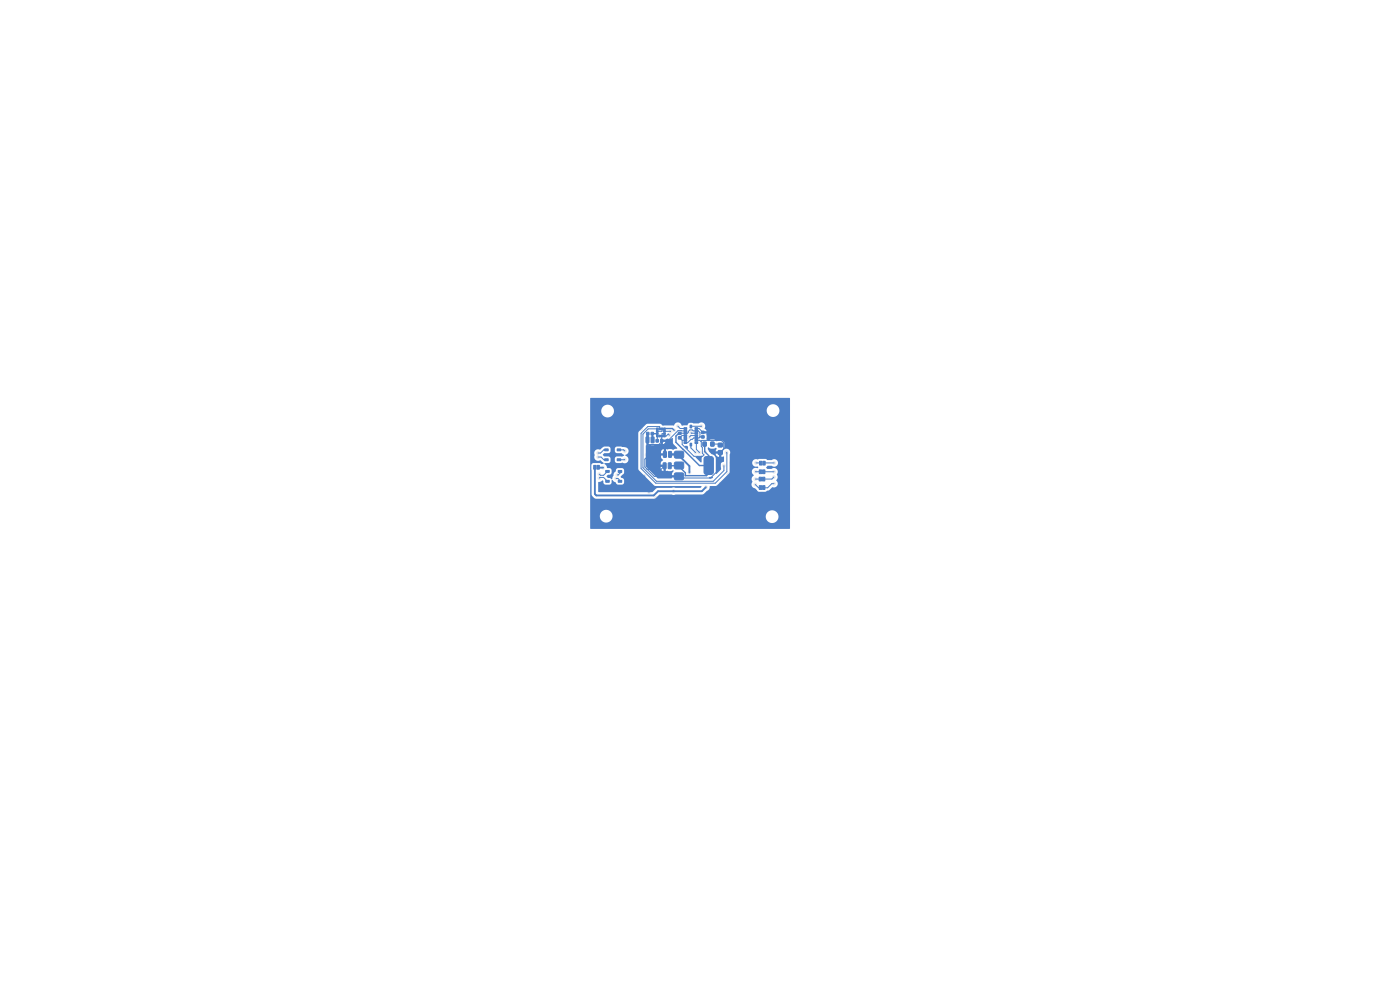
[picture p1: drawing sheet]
<svg xmlns="http://www.w3.org/2000/svg" width="297mm" height="210mm" viewBox="0 0 297 210" stroke-linecap="round" stroke-linejoin="round" font-family="sans-serif">
<g fill="#4d7fc4" stroke="#4d7fc4" stroke-width=".21">
<path d="M148.8 92.4h.6v.5h-.6z"/>
<path d="M148.8 91.5h.6v.5h-.6z"/>
<path d="M138.1 91.7h.5v.6h-.5z"/>
<path d="M137.2 91.7h.5v.6h-.5z"/>
<path d="M126.6 98.7h.6v.8h-.6z"/>
<path d="M125.9 98.7h.6v.8h-.6z"/>
<path d="M128.5 99.8h.7v.4h-.7z"/>
<path d="M131.2 99.8h.7v.4h-.7z"/>
<path d="M150.8 93.8h.7v.8h-.7z"/>
<path d="M149.1 93.8h.7v.8h-.7z"/>
<path d="M141.8 98.2l.6 .1-.1 1.1-.5-.1z"/>
<path d="M140.7 98.2l.6 .1-.1 1.1-.5-.1z"/>
<path d="M161 101.2h.6v.8h-.6z"/>
<path d="M161.7 101.2h.6v.8h-.6z"/>
<path d="M161.1 99.7h.5v.8h-.5z"/>
<path d="M161.8 99.7h.5v.8h-.5z"/>
<path d="M128.3 97.3h.7v.4h-.7z"/>
<path d="M130.9 97.3h.8v.4h-.8z"/>
<path d="M138.2 92.7l.6 .1-.1 1.1-.6-.1z"/>
<path d="M137.1 92.7l.6 .1-.1 1.1-.6-.1z"/>
<path d="M143.1 100.5l.3-.2 1.5 .1 .2 .3-.1 .9-.3 .2-1.5-.1-.2-.3z"/>
<path d="M143.1 98.2l.3-.2 1.5 .1 .2 .3-.1 .9-.3 .2-1.5-.1-.2-.3z"/>
<path d="M149.5 97l.2-.1 1.2-.1 .4 .3v3l-.2 .5h-1.4l-.3-.2-.1-3z"/>
<path d="M143.2 95.8h1.7l.2 .3-.1 .9-.3 .2-1.5-.1-.2-.3 .1-.8z"/>
<path d="M140.8 92.3h.3v.4h-.3z"/>
<path d="M140.3 92.3h.3v.4h-.3z"/>
<path d="M139.8 92.3h.3v.4h-.3z"/>
<path d="M139.3 92.3h.3v.4h-.3z"/>
<path d="M139.2 91.8h.4v.4h-.4z"/>
<path d="M139.2 91.3h.4v.4h-.4z"/>
<path d="M139.3 90.8h.3v.4h-.3z"/>
<path d="M139.8 90.8h.3v.4h-.3z"/>
<path d="M140.3 90.8h.3v.4h-.3z"/>
<path d="M140.8 90.8h.3v.4h-.3z"/>
<path d="M140.8 91.3h.4v.4h-.4z"/>
<path d="M140.8 91.8h.4v.4h-.4z"/>
<path d="M152.4 95.6h.8v.8h-.8z"/>
<path d="M152.4 94h.8v.8h-.8z"/>
<path d="M143.9 91.7h.6v.5h-.6z"/>
<path d="M143.9 92.6h.6v.5h-.6z"/>
<path d="M139.2 93.2h.5v.6h-.5z"/>
<path d="M140.1 93.2h.5v.6h-.5z"/>
<path d="M128.5 101.9h.7v.4h-.7z"/>
<path d="M131.2 101.9h.7v.4h-.7z"/>
<path d="M161.1 103h.5v.8h-.5z"/>
<path d="M161.8 103h.5v.8h-.5z"/>
<path d="M161.1 97.8h.5v.9h-.5z"/>
<path d="M161.8 97.8h.5v.9h-.5z"/>
<path d="M128.3 95.2h.7v.4h-.7z"/>
<path d="M130.9 95.2h.8v.4h-.8z"/>
<path d="M141.9 95.8l.6 .1-.1 1.1-.6-.1z"/>
<path d="M140.8 95.8l.6 .1-.1 1.1-.6-.1z"/>
<path d="M145.1 90.7h.6v.4h-.6z"/>
<path d="M145.1 91.2h.6v.4h-.6z"/>
<path d="M145.1 91.7h.6v.4h-.6z"/>
<path d="M145.1 92.2h.6v.4h-.6z"/>
<path d="M145.1 92.7h.6v.4h-.6z"/>
<path d="M145.1 93.2h.6v.4h-.6z"/>
<path d="M145.1 93.7h.6v.4h-.6z"/>
<path d="M146.4 94h.3v.6h-.3z"/>
<path d="M147.4 93.7h.6v.4h-.6z"/>
<path d="M147.4 93.2h.6v.4h-.6z"/>
<path d="M147.4 92.7h.6v.4h-.6z"/>
<path d="M147.4 92.2h.6v.4h-.6z"/>
<path d="M147.4 91.7h.6v.4h-.6z"/>
<path d="M147.4 91.2h.6v.4h-.6z"/>
<path d="M147.4 90.7h.6v.4h-.6z"/>
<path d="M146.4 90.2h.3v.6h-.3z"/>
</g>
<g fill="#ececec" stroke="#ececec" stroke-width=".21">
<circle cx="143" cy="91.3" r=".3"/>
<circle cx="149.6" cy="95.9" r=".3"/>
<circle cx="137.2" cy="85" r=".3"/>
<circle cx="152.3" cy="103.2" r=".3"/>
<circle cx="139.2" cy="106.2" r=".3"/>
<circle cx="132" cy="109.2" r=".3"/>
<circle cx="141.4" cy="88.6" r=".3"/>
<circle cx="138.4" cy="86.2" r=".3"/>
<circle cx="151.6" cy="91.2" r=".3"/>
<circle cx="154.6" cy="87.4" r=".3"/>
<circle cx="159" cy="111.6" r=".3"/>
<circle cx="161.4" cy="108" r=".3"/>
<circle cx="160" cy="89.2" r=".3"/>
<circle cx="159.4" cy="89.2" r=".3"/>
<circle cx="127" cy="90.4" r=".3"/>
<circle cx="143.8" cy="86.2" r=".3"/>
<circle cx="138.6" cy="108" r=".3"/>
<circle cx="148.8" cy="110.4" r=".3"/>
<circle cx="137.2" cy="86.8" r=".3"/>
<circle cx="138.4" cy="88" r=".3"/>
<circle cx="126.4" cy="85" r=".3"/>
<circle cx="149.8" cy="85.6" r=".3"/>
<circle cx="139.8" cy="105.6" r=".3"/>
<circle cx="154.7" cy="103.2" r=".3"/>
<circle cx="134.4" cy="109.2" r=".3"/>
<circle cx="140.8" cy="89.2" r=".3"/>
<circle cx="155.8" cy="85" r=".3"/>
<circle cx="154.6" cy="89.2" r=".3"/>
<circle cx="151" cy="86.8" r=".3"/>
<circle cx="149.8" cy="88.6" r=".3"/>
<circle cx="139" cy="85" r=".3"/>
<circle cx="136.2" cy="110.4" r=".3"/>
<circle cx="161.2" cy="85" r=".3"/>
<circle cx="143.2" cy="86.2" r=".3"/>
<circle cx="129.6" cy="106.8" r=".3"/>
<circle cx="151.6" cy="88" r=".3"/>
<circle cx="141.6" cy="107.4" r=".3"/>
<circle cx="144.4" cy="88.6" r=".3"/>
<circle cx="133.8" cy="106.8" r=".3"/>
<circle cx="133.2" cy="109.8" r=".3"/>
<circle cx="127.6" cy="90.4" r=".3"/>
<circle cx="136.8" cy="111" r=".3"/>
<circle cx="140.2" cy="89.2" r=".3"/>
<circle cx="131.8" cy="86.2" r=".3"/>
<circle cx="134.8" cy="85" r=".3"/>
<circle cx="135" cy="107.4" r=".3"/>
<circle cx="159.6" cy="107.4" r=".3"/>
<circle cx="151" cy="87.4" r=".3"/>
<circle cx="135.4" cy="85" r=".3"/>
<circle cx="132.4" cy="88.6" r=".3"/>
<circle cx="156.4" cy="85" r=".3"/>
<circle cx="125.8" cy="85.6" r=".3"/>
<circle cx="136" cy="86.2" r=".3"/>
<circle cx="146.8" cy="85.6" r=".3"/>
<circle cx="166.7" cy="85" r=".3"/>
<circle cx="154" cy="85.6" r=".3"/>
<circle cx="156.4" cy="85.6" r=".3"/>
<circle cx="141.4" cy="86.8" r=".3"/>
<circle cx="134.8" cy="89.2" r=".3"/>
<circle cx="136" cy="88.6" r=".3"/>
<circle cx="156.4" cy="88" r=".3"/>
<circle cx="152.8" cy="91.2" r=".3"/>
<circle cx="145.8" cy="111" r=".3"/>
<circle cx="138.4" cy="89.2" r=".3"/>
<circle cx="152.4" cy="111" r=".3"/>
<circle cx="160.6" cy="86.8" r=".3"/>
<circle cx="149.2" cy="88.6" r=".3"/>
<circle cx="152.8" cy="87.4" r=".3"/>
<circle cx="137.8" cy="89.2" r=".3"/>
<circle cx="136.8" cy="109.8" r=".3"/>
<circle cx="146.4" cy="109.8" r=".3"/>
<circle cx="154.2" cy="111" r=".3"/>
<circle cx="155.4" cy="106.8" r=".3"/>
<circle cx="157" cy="86.2" r=".3"/>
<circle cx="149.2" cy="88" r=".3"/>
<circle cx="131.8" cy="86.8" r=".3"/>
<circle cx="153.5" cy="104.4" r=".3"/>
<circle cx="159" cy="110.4" r=".3"/>
<circle cx="145.6" cy="86.2" r=".3"/>
<circle cx="132.4" cy="85" r=".3"/>
<circle cx="132" cy="108" r=".3"/>
<circle cx="153.6" cy="106.2" r=".3"/>
<circle cx="136.8" cy="108.6" r=".3"/>
<circle cx="151.8" cy="109.2" r=".3"/>
<circle cx="151.6" cy="85" r=".3"/>
<circle cx="138" cy="107.4" r=".3"/>
<circle cx="137.4" cy="109.2" r=".3"/>
<circle cx="138" cy="108" r=".3"/>
<circle cx="158.2" cy="86.2" r=".3"/>
<circle cx="143.2" cy="89.2" r=".3"/>
<circle cx="154.8" cy="111.6" r=".3"/>
<circle cx="158.4" cy="108.6" r=".3"/>
<circle cx="149.8" cy="85" r=".3"/>
<circle cx="155.8" cy="91.2" r=".3"/>
<circle cx="154.8" cy="109.8" r=".3"/>
<circle cx="157.6" cy="89.2" r=".3"/>
<circle cx="133.6" cy="88.6" r=".3"/>
<circle cx="153.5" cy="102.6" r=".3"/>
<circle cx="156.6" cy="109.2" r=".3"/>
<circle cx="139.2" cy="106.8" r=".3"/>
<circle cx="133" cy="90.4" r=".3"/>
<circle cx="155.3" cy="104.4" r=".3"/>
<circle cx="151.2" cy="111" r=".3"/>
<circle cx="160.2" cy="109.2" r=".3"/>
<circle cx="125.8" cy="88" r=".3"/>
<circle cx="136" cy="89.8" r=".3"/>
<circle cx="137.4" cy="107.4" r=".3"/>
<circle cx="158.2" cy="86.8" r=".3"/>
<circle cx="150.4" cy="86.2" r=".3"/>
<circle cx="142.8" cy="109.2" r=".3"/>
<circle cx="137.8" cy="87.4" r=".3"/>
<circle cx="136" cy="87.4" r=".3"/>
<circle cx="160" cy="87.4" r=".3"/>
<circle cx="159.4" cy="85.6" r=".3"/>
<circle cx="152.9" cy="102.6" r=".3"/>
<circle cx="142" cy="87.4" r=".3"/>
<circle cx="142.6" cy="88" r=".3"/>
<circle cx="155.2" cy="91.2" r=".3"/>
<circle cx="160.2" cy="111.6" r=".3"/>
<circle cx="160.4" cy="92" r=".3"/>
<circle cx="143.2" cy="88.6" r=".3"/>
<circle cx="135.4" cy="90.4" r=".3"/>
<circle cx="152.2" cy="89.2" r=".3"/>
<circle cx="166.7" cy="88.6" r=".3"/>
<circle cx="159" cy="109.2" r=".3"/>
<circle cx="139" cy="87.4" r=".3"/>
<circle cx="147.6" cy="111" r=".3"/>
<circle cx="135" cy="109.2" r=".3"/>
<circle cx="145.6" cy="87.4" r=".3"/>
<circle cx="150.4" cy="87.4" r=".3"/>
<circle cx="165.8" cy="107.4" r=".3"/>
<circle cx="154" cy="86.2" r=".3"/>
<circle cx="157" cy="85" r=".3"/>
<circle cx="157.2" cy="109.8" r=".3"/>
<circle cx="143.2" cy="87.4" r=".3"/>
<circle cx="140.2" cy="88.6" r=".3"/>
<circle cx="152.9" cy="103.2" r=".3"/>
<circle cx="159.6" cy="110.4" r=".3"/>
<circle cx="166.7" cy="86.2" r=".3"/>
<circle cx="154" cy="85" r=".3"/>
<circle cx="143.2" cy="85" r=".3"/>
<circle cx="151.6" cy="89.2" r=".3"/>
<circle cx="139.8" cy="109.2" r=".3"/>
<circle cx="148.8" cy="111.6" r=".3"/>
<circle cx="157" cy="88" r=".3"/>
<circle cx="133.2" cy="111" r=".3"/>
<circle cx="156" cy="109.2" r=".3"/>
<circle cx="137.4" cy="106.2" r=".3"/>
<circle cx="160.6" cy="88.6" r=".3"/>
<circle cx="125.8" cy="89.2" r=".3"/>
<circle cx="145.8" cy="110.4" r=".3"/>
<circle cx="154.8" cy="108.6" r=".3"/>
<circle cx="151.8" cy="111.6" r=".3"/>
<circle cx="136" cy="85" r=".3"/>
<circle cx="134.2" cy="85" r=".3"/>
<circle cx="158.8" cy="85.6" r=".3"/>
<circle cx="155.1" cy="101.2" r=".3"/>
<circle cx="157.8" cy="108" r=".3"/>
<circle cx="138.4" cy="85" r=".3"/>
<circle cx="137.8" cy="86.2" r=".3"/>
<circle cx="132" cy="108.6" r=".3"/>
<circle cx="152.9" cy="105" r=".3"/>
<circle cx="143.4" cy="110.4" r=".3"/>
<circle cx="153.6" cy="109.2" r=".3"/>
<circle cx="154" cy="88" r=".3"/>
<circle cx="167" cy="108" r=".3"/>
<circle cx="150.4" cy="88" r=".3"/>
<circle cx="153.6" cy="106.8" r=".3"/>
<circle cx="139.6" cy="85.6" r=".3"/>
<circle cx="132" cy="111" r=".3"/>
<circle cx="142.6" cy="88.6" r=".3"/>
<circle cx="145.6" cy="85" r=".3"/>
<circle cx="136.6" cy="85.6" r=".3"/>
<circle cx="148" cy="87.4" r=".3"/>
<circle cx="155.2" cy="85.6" r=".3"/>
<circle cx="133" cy="85" r=".3"/>
<circle cx="146.2" cy="85.6" r=".3"/>
<circle cx="126.4" cy="90.4" r=".3"/>
<circle cx="141.4" cy="85.6" r=".3"/>
<circle cx="166.1" cy="85" r=".3"/>
<circle cx="160" cy="88.6" r=".3"/>
<circle cx="161.8" cy="85" r=".3"/>
<circle cx="137.8" cy="88.6" r=".3"/>
<circle cx="135.6" cy="111.6" r=".3"/>
<circle cx="126" cy="106.8" r=".3"/>
<circle cx="152.8" cy="85.6" r=".3"/>
<circle cx="145" cy="86.2" r=".3"/>
<circle cx="155.4" cy="111" r=".3"/>
<circle cx="156" cy="107.4" r=".3"/>
<circle cx="145" cy="88" r=".3"/>
<circle cx="132" cy="106.8" r=".3"/>
<circle cx="141.6" cy="111.6" r=".3"/>
<circle cx="152.2" cy="87.4" r=".3"/>
<circle cx="153.5" cy="105.6" r=".3"/>
<circle cx="137.4" cy="111" r=".3"/>
<circle cx="144.4" cy="88" r=".3"/>
<circle cx="138" cy="111.6" r=".3"/>
<circle cx="154.2" cy="106.8" r=".3"/>
<circle cx="142.8" cy="110.4" r=".3"/>
<circle cx="145" cy="87.4" r=".3"/>
<circle cx="142.6" cy="85" r=".3"/>
<circle cx="160.8" cy="109.2" r=".3"/>
<circle cx="157" cy="86.8" r=".3"/>
<circle cx="144.6" cy="111" r=".3"/>
<circle cx="138.4" cy="85.6" r=".3"/>
<circle cx="140.4" cy="109.2" r=".3"/>
<circle cx="139" cy="88" r=".3"/>
<circle cx="136.6" cy="85" r=".3"/>
<circle cx="149.2" cy="86.8" r=".3"/>
<circle cx="159" cy="109.8" r=".3"/>
<circle cx="155.4" cy="110.4" r=".3"/>
<circle cx="132.4" cy="86.8" r=".3"/>
<circle cx="141" cy="109.2" r=".3"/>
<circle cx="157.6" cy="85.6" r=".3"/>
<circle cx="159.6" cy="108" r=".3"/>
<circle cx="131.8" cy="88" r=".3"/>
<circle cx="132.6" cy="109.2" r=".3"/>
<circle cx="157.8" cy="109.8" r=".3"/>
<circle cx="143.8" cy="88.6" r=".3"/>
<circle cx="130.8" cy="106.8" r=".3"/>
<circle cx="156.6" cy="109.8" r=".3"/>
<circle cx="143.4" cy="109.8" r=".3"/>
<circle cx="136.6" cy="89.2" r=".3"/>
<circle cx="131.8" cy="85.6" r=".3"/>
<circle cx="138.6" cy="107.4" r=".3"/>
<circle cx="139.6" cy="86.8" r=".3"/>
<circle cx="148.2" cy="111" r=".3"/>
<circle cx="141.6" cy="106.2" r=".3"/>
<circle cx="153" cy="111.6" r=".3"/>
<circle cx="136" cy="88" r=".3"/>
<circle cx="132.4" cy="87.4" r=".3"/>
<circle cx="130.6" cy="89.8" r=".3"/>
<circle cx="147" cy="109.8" r=".3"/>
<circle cx="152.4" cy="110.4" r=".3"/>
<circle cx="136.8" cy="107.4" r=".3"/>
<circle cx="158.4" cy="109.2" r=".3"/>
<circle cx="154.2" cy="108" r=".3"/>
<circle cx="127" cy="85" r=".3"/>
<circle cx="153" cy="109.8" r=".3"/>
<circle cx="157.2" cy="110.4" r=".3"/>
<circle cx="159" cy="108.6" r=".3"/>
<circle cx="137.2" cy="96.5" r=".3"/>
<circle cx="154" cy="89.2" r=".3"/>
<circle cx="127.6" cy="91" r=".3"/>
<circle cx="139" cy="88.6" r=".3"/>
<circle cx="132.6" cy="108.6" r=".3"/>
<circle cx="135.6" cy="107.4" r=".3"/>
<circle cx="150.6" cy="110.4" r=".3"/>
<circle cx="144" cy="111" r=".3"/>
<circle cx="136.8" cy="106.2" r=".3"/>
<circle cx="166.4" cy="111.6" r=".3"/>
<circle cx="160.6" cy="86.2" r=".3"/>
<circle cx="156.4" cy="88.6" r=".3"/>
<circle cx="148.6" cy="89.2" r=".3"/>
<circle cx="125.8" cy="87.4" r=".3"/>
<circle cx="146.8" cy="88" r=".3"/>
<circle cx="154.8" cy="106.2" r=".3"/>
<circle cx="150.6" cy="109.8" r=".3"/>
<circle cx="158.8" cy="89.2" r=".3"/>
<circle cx="152.8" cy="88" r=".3"/>
<circle cx="135.4" cy="89.2" r=".3"/>
<circle cx="131.2" cy="85" r=".3"/>
<circle cx="157.2" cy="108.6" r=".3"/>
<circle cx="136.2" cy="106.8" r=".3"/>
<circle cx="157.6" cy="85" r=".3"/>
<circle cx="155.2" cy="87.4" r=".3"/>
<circle cx="159.4" cy="86.8" r=".3"/>
<circle cx="156" cy="109.8" r=".3"/>
<circle cx="155.3" cy="105.6" r=".3"/>
<circle cx="153.6" cy="110.4" r=".3"/>
<circle cx="155.7" cy="101.2" r=".3"/>
<circle cx="154.7" cy="105" r=".3"/>
<circle cx="126" cy="111" r=".3"/>
<circle cx="148.6" cy="86.2" r=".3"/>
<circle cx="167" cy="111.6" r=".3"/>
<circle cx="131.2" cy="90.4" r=".3"/>
<circle cx="145.2" cy="109.8" r=".3"/>
<circle cx="138.6" cy="109.2" r=".3"/>
<circle cx="137.2" cy="89.2" r=".3"/>
<circle cx="150.6" cy="111" r=".3"/>
<circle cx="136.2" cy="109.8" r=".3"/>
<circle cx="157.6" cy="88.6" r=".3"/>
<circle cx="128.2" cy="91" r=".3"/>
<circle cx="166.4" cy="108" r=".3"/>
<circle cx="151.2" cy="110.4" r=".3"/>
<circle cx="138.6" cy="111" r=".3"/>
<circle cx="135" cy="108" r=".3"/>
<circle cx="136.8" cy="106.8" r=".3"/>
<circle cx="155.4" cy="108.6" r=".3"/>
<circle cx="151.6" cy="85.6" r=".3"/>
<circle cx="130.2" cy="106.8" r=".3"/>
<circle cx="136.6" cy="88.6" r=".3"/>
<circle cx="132.4" cy="86.2" r=".3"/>
<circle cx="158.8" cy="86.2" r=".3"/>
<circle cx="146.2" cy="86.2" r=".3"/>
<circle cx="134.8" cy="89.8" r=".3"/>
<circle cx="156.4" cy="86.2" r=".3"/>
<circle cx="157" cy="89.2" r=".3"/>
<circle cx="156.6" cy="108.6" r=".3"/>
<circle cx="153.6" cy="109.8" r=".3"/>
<circle cx="144.4" cy="89.2" r=".3"/>
<circle cx="157.2" cy="111" r=".3"/>
<circle cx="159.6" cy="111" r=".3"/>
<circle cx="145" cy="85" r=".3"/>
<circle cx="148.2" cy="109.8" r=".3"/>
<circle cx="137.2" cy="86.2" r=".3"/>
<circle cx="149.8" cy="86.8" r=".3"/>
<circle cx="129.4" cy="90.4" r=".3"/>
<circle cx="157.8" cy="109.2" r=".3"/>
<circle cx="166.4" cy="107.4" r=".3"/>
<circle cx="139.8" cy="111" r=".3"/>
<circle cx="158.4" cy="111.6" r=".3"/>
<circle cx="160" cy="86.2" r=".3"/>
<circle cx="136.7" cy="101" r=".3"/>
<circle cx="132.4" cy="88" r=".3"/>
<circle cx="131.8" cy="89.2" r=".3"/>
<circle cx="133.6" cy="85" r=".3"/>
<circle cx="145" cy="86.8" r=".3"/>
<circle cx="139.2" cy="110.4" r=".3"/>
<circle cx="152.8" cy="86.2" r=".3"/>
<circle cx="154.2" cy="106.2" r=".3"/>
<circle cx="131.4" cy="108.6" r=".3"/>
<circle cx="126.6" cy="111.6" r=".3"/>
<circle cx="155.2" cy="88" r=".3"/>
<circle cx="152.4" cy="109.8" r=".3"/>
<circle cx="155.8" cy="86.8" r=".3"/>
<circle cx="134.2" cy="85.6" r=".3"/>
<circle cx="133.8" cy="107.4" r=".3"/>
<circle cx="167" cy="109.8" r=".3"/>
<circle cx="151" cy="85.6" r=".3"/>
<circle cx="131.4" cy="111" r=".3"/>
<circle cx="128.2" cy="90.4" r=".3"/>
<circle cx="131.2" cy="91" r=".3"/>
<circle cx="133.2" cy="111.6" r=".3"/>
<circle cx="138.6" cy="111.6" r=".3"/>
<circle cx="131.4" cy="107.4" r=".3"/>
<circle cx="151.6" cy="86.8" r=".3"/>
<circle cx="143.4" cy="109.2" r=".3"/>
<circle cx="134.4" cy="107.4" r=".3"/>
<circle cx="146.8" cy="86.2" r=".3"/>
<circle cx="141.4" cy="87.4" r=".3"/>
<circle cx="154.1" cy="103.8" r=".3"/>
<circle cx="155.8" cy="86.2" r=".3"/>
<circle cx="154.1" cy="105" r=".3"/>
<circle cx="155.7" cy="98.2" r=".3"/>
<circle cx="142" cy="85.6" r=".3"/>
<circle cx="167" cy="111" r=".3"/>
<circle cx="133" cy="85.6" r=".3"/>
<circle cx="155.7" cy="100.6" r=".3"/>
<circle cx="156.4" cy="86.8" r=".3"/>
<circle cx="154.2" cy="110.4" r=".3"/>
<circle cx="134.8" cy="85.6" r=".3"/>
<circle cx="140.4" cy="105.6" r=".3"/>
<circle cx="161.2" cy="87.4" r=".3"/>
<circle cx="146.4" cy="111.6" r=".3"/>
<circle cx="137.8" cy="85" r=".3"/>
<circle cx="155.2" cy="85" r=".3"/>
<circle cx="136.6" cy="86.2" r=".3"/>
<circle cx="160.6" cy="88" r=".3"/>
<circle cx="130.6" cy="91" r=".3"/>
<circle cx="138" cy="111" r=".3"/>
<circle cx="127" cy="89.8" r=".3"/>
<circle cx="156" cy="108" r=".3"/>
<circle cx="138.4" cy="87.4" r=".3"/>
<circle cx="141" cy="107.4" r=".3"/>
<circle cx="128.8" cy="91" r=".3"/>
<circle cx="142.6" cy="86.8" r=".3"/>
<circle cx="149.4" cy="111.6" r=".3"/>
<circle cx="133.6" cy="86.8" r=".3"/>
<circle cx="139.2" cy="108.6" r=".3"/>
<circle cx="148.2" cy="110.4" r=".3"/>
<circle cx="157.6" cy="86.8" r=".3"/>
<circle cx="160.8" cy="109.8" r=".3"/>
<circle cx="145.8" cy="109.8" r=".3"/>
<circle cx="125.8" cy="86.2" r=".3"/>
<circle cx="160.8" cy="107.4" r=".3"/>
<circle cx="157.6" cy="88" r=".3"/>
<circle cx="146.2" cy="87.4" r=".3"/>
<circle cx="148.2" cy="109.2" r=".3"/>
<circle cx="133.6" cy="89.8" r=".3"/>
<circle cx="137.4" cy="109.8" r=".3"/>
<circle cx="139.2" cy="109.2" r=".3"/>
<circle cx="153.6" cy="108" r=".3"/>
<circle cx="151.2" cy="92.4" r=".3"/>
<circle cx="139" cy="89.2" r=".3"/>
<circle cx="133" cy="89.2" r=".3"/>
<circle cx="149.4" cy="109.8" r=".3"/>
<circle cx="154.8" cy="110.4" r=".3"/>
<circle cx="156" cy="111" r=".3"/>
<circle cx="141.6" cy="106.8" r=".3"/>
<circle cx="160.2" cy="107.4" r=".3"/>
<circle cx="131.8" cy="91" r=".3"/>
<circle cx="150.4" cy="85" r=".3"/>
<circle cx="151" cy="88.6" r=".3"/>
<circle cx="154.6" cy="88.6" r=".3"/>
<circle cx="140.4" cy="107.4" r=".3"/>
<circle cx="130.8" cy="107.4" r=".3"/>
<circle cx="149.2" cy="85" r=".3"/>
<circle cx="147" cy="109.2" r=".3"/>
<circle cx="145.2" cy="111.6" r=".3"/>
<circle cx="134.2" cy="90.4" r=".3"/>
<circle cx="141.4" cy="85" r=".3"/>
<circle cx="139.2" cy="105.6" r=".3"/>
<circle cx="135" cy="106.8" r=".3"/>
<circle cx="135" cy="108.6" r=".3"/>
<circle cx="134.2" cy="89.8" r=".3"/>
<circle cx="153.4" cy="89.2" r=".3"/>
<circle cx="157.8" cy="108.6" r=".3"/>
<circle cx="148.6" cy="88.6" r=".3"/>
<circle cx="143.8" cy="87.4" r=".3"/>
<circle cx="158.4" cy="110.4" r=".3"/>
<circle cx="133.2" cy="110.4" r=".3"/>
<circle cx="136.2" cy="107.4" r=".3"/>
<circle cx="155.7" cy="100" r=".3"/>
<circle cx="135.6" cy="111" r=".3"/>
<circle cx="161.2" cy="86.2" r=".3"/>
<circle cx="146.2" cy="89.2" r=".3"/>
<circle cx="151" cy="85" r=".3"/>
<circle cx="156" cy="111.6" r=".3"/>
<circle cx="136.6" cy="88" r=".3"/>
<circle cx="148.8" cy="109.8" r=".3"/>
<circle cx="150" cy="111" r=".3"/>
<circle cx="148.6" cy="85" r=".3"/>
<circle cx="158.2" cy="85.6" r=".3"/>
<circle cx="139.2" cy="111" r=".3"/>
<circle cx="140.8" cy="88" r=".3"/>
<circle cx="135.4" cy="85.6" r=".3"/>
<circle cx="145.6" cy="86.8" r=".3"/>
<circle cx="133" cy="89.8" r=".3"/>
<circle cx="125.8" cy="86.8" r=".3"/>
<circle cx="132" cy="107.4" r=".3"/>
<circle cx="159.4" cy="87.4" r=".3"/>
<circle cx="136.8" cy="108" r=".3"/>
<circle cx="152.3" cy="103.8" r=".3"/>
<circle cx="133.2" cy="106.8" r=".3"/>
<circle cx="140.4" cy="109.8" r=".3"/>
<circle cx="140.8" cy="85" r=".3"/>
<circle cx="139.2" cy="109.8" r=".3"/>
<circle cx="145.2" cy="111" r=".3"/>
<circle cx="144.6" cy="109.2" r=".3"/>
<circle cx="135.6" cy="106.8" r=".3"/>
<circle cx="147.4" cy="87.4" r=".3"/>
<circle cx="167" cy="110.4" r=".3"/>
<circle cx="145.8" cy="109.2" r=".3"/>
<circle cx="130.8" cy="111.6" r=".3"/>
<circle cx="158.2" cy="87.4" r=".3"/>
<circle cx="136.2" cy="111" r=".3"/>
<circle cx="152.2" cy="85" r=".3"/>
<circle cx="154.8" cy="107.4" r=".3"/>
<circle cx="142" cy="85" r=".3"/>
<circle cx="138.6" cy="106.2" r=".3"/>
<circle cx="136.8" cy="109.2" r=".3"/>
<circle cx="153.4" cy="86.2" r=".3"/>
<circle cx="139.6" cy="89.2" r=".3"/>
<circle cx="136.6" cy="87.4" r=".3"/>
<circle cx="158.8" cy="88" r=".3"/>
<circle cx="150" cy="109.8" r=".3"/>
<circle cx="165.8" cy="111.6" r=".3"/>
<circle cx="146.8" cy="85" r=".3"/>
<circle cx="134.2" cy="86.2" r=".3"/>
<circle cx="153.4" cy="91.2" r=".3"/>
<circle cx="130.6" cy="90.4" r=".3"/>
<circle cx="131.2" cy="89.8" r=".3"/>
<circle cx="133.6" cy="87.4" r=".3"/>
<circle cx="142.2" cy="110.4" r=".3"/>
<circle cx="155.8" cy="89.2" r=".3"/>
<circle cx="159.4" cy="88.6" r=".3"/>
<circle cx="141.6" cy="108.6" r=".3"/>
<circle cx="148" cy="85.6" r=".3"/>
<circle cx="135.6" cy="109.2" r=".3"/>
<circle cx="151.6" cy="86.2" r=".3"/>
<circle cx="138" cy="106.8" r=".3"/>
<circle cx="161.2" cy="85.6" r=".3"/>
<circle cx="143.8" cy="85" r=".3"/>
<circle cx="132.6" cy="109.8" r=".3"/>
<circle cx="139" cy="86.8" r=".3"/>
<circle cx="141" cy="111.6" r=".3"/>
<circle cx="127.2" cy="106.8" r=".3"/>
<circle cx="133.6" cy="88" r=".3"/>
<circle cx="157.2" cy="108" r=".3"/>
<circle cx="161.4" cy="111" r=".3"/>
<circle cx="126.4" cy="88.6" r=".3"/>
<circle cx="137.4" cy="106.8" r=".3"/>
<circle cx="161.8" cy="89.2" r=".3"/>
<circle cx="151.2" cy="111.6" r=".3"/>
<circle cx="150" cy="111.6" r=".3"/>
<circle cx="139.8" cy="108.6" r=".3"/>
<circle cx="150.4" cy="88.6" r=".3"/>
<circle cx="134.4" cy="111.6" r=".3"/>
<circle cx="149.8" cy="88" r=".3"/>
<circle cx="134.8" cy="86.8" r=".3"/>
<circle cx="146.2" cy="85" r=".3"/>
<circle cx="151" cy="89.2" r=".3"/>
<circle cx="161.2" cy="88" r=".3"/>
<circle cx="154.8" cy="109.2" r=".3"/>
<circle cx="155.3" cy="105" r=".3"/>
<circle cx="137.8" cy="88" r=".3"/>
<circle cx="134.2" cy="86.8" r=".3"/>
<circle cx="150.4" cy="86.8" r=".3"/>
<circle cx="142.8" cy="109.8" r=".3"/>
<circle cx="153.5" cy="103.8" r=".3"/>
<circle cx="154.5" cy="101.2" r=".3"/>
<circle cx="143.8" cy="86.8" r=".3"/>
<circle cx="132" cy="109.8" r=".3"/>
<circle cx="150.6" cy="109.2" r=".3"/>
<circle cx="136.2" cy="109.2" r=".3"/>
<circle cx="154.5" cy="100.6" r=".3"/>
<circle cx="142.6" cy="85.6" r=".3"/>
<circle cx="144" cy="110.4" r=".3"/>
<circle cx="134.8" cy="86.2" r=".3"/>
<circle cx="161.2" cy="86.8" r=".3"/>
<circle cx="131.4" cy="111.6" r=".3"/>
<circle cx="156.4" cy="87.4" r=".3"/>
<circle cx="160.6" cy="85" r=".3"/>
<circle cx="126.4" cy="89.2" r=".3"/>
<circle cx="160.6" cy="87.4" r=".3"/>
<circle cx="142.2" cy="109.8" r=".3"/>
<circle cx="153.4" cy="88.6" r=".3"/>
<circle cx="134.4" cy="111" r=".3"/>
<circle cx="126.4" cy="85.6" r=".3"/>
<circle cx="161.4" cy="107.4" r=".3"/>
<circle cx="147.4" cy="85" r=".3"/>
<circle cx="133.2" cy="107.4" r=".3"/>
<circle cx="156" cy="108.6" r=".3"/>
<circle cx="133.6" cy="85.6" r=".3"/>
<circle cx="151" cy="86.2" r=".3"/>
<circle cx="144.4" cy="85" r=".3"/>
<circle cx="159" cy="111" r=".3"/>
<circle cx="134.8" cy="90.4" r=".3"/>
<circle cx="153.4" cy="85" r=".3"/>
<circle cx="159.4" cy="85" r=".3"/>
<circle cx="155.4" cy="108" r=".3"/>
<circle cx="137.2" cy="88" r=".3"/>
<circle cx="152.2" cy="85.6" r=".3"/>
<circle cx="136" cy="89.2" r=".3"/>
<circle cx="132" cy="110.4" r=".3"/>
<circle cx="136" cy="86.8" r=".3"/>
<circle cx="153.4" cy="86.8" r=".3"/>
<circle cx="141.6" cy="109.8" r=".3"/>
<circle cx="153" cy="92.4" r=".3"/>
<circle cx="135" cy="110.4" r=".3"/>
<circle cx="139.6" cy="88" r=".3"/>
<circle cx="133" cy="91" r=".3"/>
<circle cx="148" cy="86.8" r=".3"/>
<circle cx="133.8" cy="109.2" r=".3"/>
<circle cx="146.4" cy="111" r=".3"/>
<circle cx="135.4" cy="86.8" r=".3"/>
<circle cx="141" cy="105.6" r=".3"/>
<circle cx="155.1" cy="98.2" r=".3"/>
<circle cx="142" cy="88" r=".3"/>
<circle cx="145.6" cy="88.6" r=".3"/>
<circle cx="153.5" cy="105" r=".3"/>
<circle cx="139.2" cy="111.6" r=".3"/>
<circle cx="166.4" cy="108.6" r=".3"/>
<circle cx="152.9" cy="105.6" r=".3"/>
<circle cx="154.1" cy="105.6" r=".3"/>
<circle cx="156.6" cy="111.6" r=".3"/>
<circle cx="154.8" cy="106.8" r=".3"/>
<circle cx="132.4" cy="89.8" r=".3"/>
<circle cx="126.6" cy="107.4" r=".3"/>
<circle cx="131.8" cy="87.4" r=".3"/>
<circle cx="132.6" cy="108" r=".3"/>
<circle cx="126.4" cy="89.8" r=".3"/>
<circle cx="161.4" cy="111.6" r=".3"/>
<circle cx="133.6" cy="90.4" r=".3"/>
<circle cx="155.8" cy="87.4" r=".3"/>
<circle cx="138.6" cy="110.4" r=".3"/>
<circle cx="144" cy="109.2" r=".3"/>
<circle cx="130" cy="91" r=".3"/>
<circle cx="146.8" cy="88.6" r=".3"/>
<circle cx="137.4" cy="108.6" r=".3"/>
<circle cx="126.4" cy="91" r=".3"/>
<circle cx="150.4" cy="85.6" r=".3"/>
<circle cx="156.6" cy="110.4" r=".3"/>
<circle cx="160.2" cy="110.4" r=".3"/>
<circle cx="154.2" cy="108.6" r=".3"/>
<circle cx="139" cy="86.2" r=".3"/>
<circle cx="158.2" cy="88" r=".3"/>
<circle cx="141" cy="111" r=".3"/>
<circle cx="144.4" cy="86.2" r=".3"/>
<circle cx="141.4" cy="86.2" r=".3"/>
<circle cx="150.6" cy="92.4" r=".3"/>
<circle cx="160" cy="85" r=".3"/>
<circle cx="154.7" cy="104.4" r=".3"/>
<circle cx="134.4" cy="108.6" r=".3"/>
<circle cx="155.1" cy="100" r=".3"/>
<circle cx="146.4" cy="110.4" r=".3"/>
<circle cx="131.4" cy="109.8" r=".3"/>
<circle cx="160.8" cy="111" r=".3"/>
<circle cx="133" cy="88" r=".3"/>
<circle cx="161.2" cy="88.6" r=".3"/>
<circle cx="131.8" cy="89.8" r=".3"/>
<circle cx="158.8" cy="87.4" r=".3"/>
<circle cx="140.8" cy="85.6" r=".3"/>
<circle cx="148.6" cy="88" r=".3"/>
<circle cx="159.4" cy="88" r=".3"/>
<circle cx="143.4" cy="111.6" r=".3"/>
<circle cx="139.8" cy="106.2" r=".3"/>
<circle cx="148" cy="86.2" r=".3"/>
<circle cx="156.6" cy="111" r=".3"/>
<circle cx="134.2" cy="87.4" r=".3"/>
<circle cx="146.4" cy="109.2" r=".3"/>
<circle cx="155.8" cy="85.6" r=".3"/>
<circle cx="142.6" cy="89.2" r=".3"/>
<circle cx="152.8" cy="86.8" r=".3"/>
<circle cx="166" cy="89.2" r=".3"/>
<circle cx="127.6" cy="89.8" r=".3"/>
<circle cx="131.4" cy="108" r=".3"/>
<circle cx="147.4" cy="86.2" r=".3"/>
<circle cx="146.8" cy="89.2" r=".3"/>
<circle cx="157" cy="88.6" r=".3"/>
<circle cx="154.2" cy="109.8" r=".3"/>
<circle cx="157.2" cy="109.2" r=".3"/>
<circle cx="139.2" cy="107.4" r=".3"/>
<circle cx="141.6" cy="111" r=".3"/>
<circle cx="133.6" cy="86.2" r=".3"/>
<circle cx="155.2" cy="86.2" r=".3"/>
<circle cx="132.6" cy="107.4" r=".3"/>
<circle cx="140.4" cy="108.6" r=".3"/>
<circle cx="138" cy="109.2" r=".3"/>
<circle cx="160.6" cy="89.2" r=".3"/>
<circle cx="125.8" cy="88.6" r=".3"/>
<circle cx="152.2" cy="88.6" r=".3"/>
<circle cx="154.2" cy="107.4" r=".3"/>
<circle cx="149.8" cy="86.2" r=".3"/>
<circle cx="145.6" cy="89.2" r=".3"/>
<circle cx="141" cy="106.8" r=".3"/>
<circle cx="134.4" cy="106.8" r=".3"/>
<circle cx="155.1" cy="100.6" r=".3"/>
<circle cx="144.4" cy="85.6" r=".3"/>
<circle cx="155.4" cy="106.2" r=".3"/>
<circle cx="153.5" cy="103.2" r=".3"/>
<circle cx="154" cy="88.6" r=".3"/>
<circle cx="154.8" cy="108" r=".3"/>
<circle cx="151" cy="91.2" r=".3"/>
<circle cx="158.8" cy="85" r=".3"/>
<circle cx="148" cy="89.2" r=".3"/>
<circle cx="158.2" cy="89.2" r=".3"/>
<circle cx="150" cy="109.2" r=".3"/>
<circle cx="148.8" cy="111" r=".3"/>
<circle cx="141.4" cy="88" r=".3"/>
<circle cx="145.8" cy="111.6" r=".3"/>
<circle cx="157.8" cy="110.4" r=".3"/>
<circle cx="147.4" cy="88" r=".3"/>
<circle cx="153.6" cy="111.6" r=".3"/>
<circle cx="155.7" cy="98.8" r=".3"/>
<circle cx="154" cy="86.8" r=".3"/>
<circle cx="154.1" cy="102.6" r=".3"/>
<circle cx="140.4" cy="111" r=".3"/>
<circle cx="142.2" cy="111.6" r=".3"/>
<circle cx="154.6" cy="85" r=".3"/>
<circle cx="151.6" cy="88.6" r=".3"/>
<circle cx="142" cy="86.8" r=".3"/>
<circle cx="154.7" cy="105.6" r=".3"/>
<circle cx="133" cy="88.6" r=".3"/>
<circle cx="137.2" cy="85.6" r=".3"/>
<circle cx="132.4" cy="91" r=".3"/>
<circle cx="128.8" cy="90.4" r=".3"/>
<circle cx="147" cy="110.4" r=".3"/>
<circle cx="147.6" cy="110.4" r=".3"/>
<circle cx="132.4" cy="90.4" r=".3"/>
<circle cx="155.4" cy="111.6" r=".3"/>
<circle cx="148" cy="85" r=".3"/>
<circle cx="166.7" cy="89.2" r=".3"/>
<circle cx="153.4" cy="88" r=".3"/>
<circle cx="152.2" cy="91.2" r=".3"/>
<circle cx="140.2" cy="87.4" r=".3"/>
<circle cx="139.8" cy="109.8" r=".3"/>
<circle cx="139.6" cy="85" r=".3"/>
<circle cx="152.4" cy="92.4" r=".3"/>
<circle cx="125.8" cy="89.8" r=".3"/>
<circle cx="146.2" cy="88" r=".3"/>
<circle cx="136.2" cy="108" r=".3"/>
<circle cx="125.8" cy="85" r=".3"/>
<circle cx="133.2" cy="108" r=".3"/>
<circle cx="141" cy="106.2" r=".3"/>
<circle cx="138" cy="109.8" r=".3"/>
<circle cx="155.3" cy="103.8" r=".3"/>
<circle cx="142.2" cy="109.2" r=".3"/>
<circle cx="133.8" cy="110.4" r=".3"/>
<circle cx="155.8" cy="88.6" r=".3"/>
<circle cx="152.2" cy="86.2" r=".3"/>
<circle cx="126" cy="107.4" r=".3"/>
<circle cx="140.2" cy="86.8" r=".3"/>
<circle cx="148" cy="88" r=".3"/>
<circle cx="140.8" cy="86.2" r=".3"/>
<circle cx="127" cy="91" r=".3"/>
<circle cx="154.6" cy="86.8" r=".3"/>
<circle cx="141" cy="110.4" r=".3"/>
<circle cx="131.4" cy="109.2" r=".3"/>
<circle cx="151.8" cy="111" r=".3"/>
<circle cx="143.4" cy="111" r=".3"/>
<circle cx="152.4" cy="109.2" r=".3"/>
<circle cx="140.4" cy="106.2" r=".3"/>
<circle cx="154.7" cy="103.8" r=".3"/>
<circle cx="132.4" cy="89.2" r=".3"/>
<circle cx="134.4" cy="109.8" r=".3"/>
<circle cx="131.8" cy="90.4" r=".3"/>
<circle cx="157.8" cy="111" r=".3"/>
<circle cx="142.6" cy="86.2" r=".3"/>
<circle cx="150.6" cy="111.6" r=".3"/>
<circle cx="140.2" cy="85.6" r=".3"/>
<circle cx="141.6" cy="105.6" r=".3"/>
<circle cx="142.6" cy="87.4" r=".3"/>
<circle cx="157.8" cy="111.6" r=".3"/>
<circle cx="167" cy="109.2" r=".3"/>
<circle cx="155.2" cy="88.6" r=".3"/>
<circle cx="152.8" cy="89.2" r=".3"/>
<circle cx="148.6" cy="85.6" r=".3"/>
<circle cx="152.9" cy="104.4" r=".3"/>
<circle cx="134.2" cy="88" r=".3"/>
<circle cx="139.6" cy="86.2" r=".3"/>
<circle cx="134.4" cy="110.4" r=".3"/>
<circle cx="146.8" cy="87.4" r=".3"/>
<circle cx="137.2" cy="87.4" r=".3"/>
<circle cx="137.7" cy="104.4" r=".3"/>
<circle cx="153" cy="110.4" r=".3"/>
<circle cx="145" cy="88.6" r=".3"/>
<circle cx="160.8" cy="111.6" r=".3"/>
<circle cx="140.8" cy="86.8" r=".3"/>
<circle cx="156" cy="110.4" r=".3"/>
<circle cx="139.6" cy="87.4" r=".3"/>
<circle cx="157" cy="87.4" r=".3"/>
<circle cx="149.4" cy="110.4" r=".3"/>
<circle cx="160.8" cy="108" r=".3"/>
<circle cx="132" cy="111.6" r=".3"/>
<circle cx="142.2" cy="111" r=".3"/>
<circle cx="133.8" cy="109.8" r=".3"/>
<circle cx="133.8" cy="108.6" r=".3"/>
<circle cx="151" cy="88" r=".3"/>
<circle cx="158.4" cy="109.8" r=".3"/>
<circle cx="160.8" cy="110.4" r=".3"/>
<circle cx="153.4" cy="87.4" r=".3"/>
<circle cx="151.2" cy="109.8" r=".3"/>
<circle cx="155.4" cy="109.8" r=".3"/>
<circle cx="151.2" cy="109.2" r=".3"/>
<circle cx="155.7" cy="99.4" r=".3"/>
<circle cx="136.6" cy="86.8" r=".3"/>
<circle cx="167" cy="108.6" r=".3"/>
<circle cx="135" cy="109.8" r=".3"/>
<circle cx="152.8" cy="85" r=".3"/>
<circle cx="159.6" cy="109.2" r=".3"/>
<circle cx="147.6" cy="109.8" r=".3"/>
<circle cx="141.4" cy="89.2" r=".3"/>
<circle cx="138.6" cy="108.6" r=".3"/>
<circle cx="135" cy="111.6" r=".3"/>
<circle cx="143.2" cy="88" r=".3"/>
<circle cx="144" cy="109.8" r=".3"/>
<circle cx="147.4" cy="86.8" r=".3"/>
<circle cx="133.2" cy="108.6" r=".3"/>
<circle cx="153.6" cy="111" r=".3"/>
<circle cx="140.2" cy="85" r=".3"/>
<circle cx="135.6" cy="109.8" r=".3"/>
<circle cx="135.6" cy="110.4" r=".3"/>
<circle cx="152.9" cy="103.8" r=".3"/>
<circle cx="138.6" cy="109.8" r=".3"/>
<circle cx="149.8" cy="89.2" r=".3"/>
<circle cx="133.2" cy="109.2" r=".3"/>
<circle cx="144.6" cy="111.6" r=".3"/>
<circle cx="135.6" cy="108" r=".3"/>
<circle cx="157.6" cy="86.2" r=".3"/>
<circle cx="154.6" cy="86.2" r=".3"/>
<circle cx="149.2" cy="86.2" r=".3"/>
<circle cx="154.1" cy="104.4" r=".3"/>
<circle cx="126.6" cy="106.8" r=".3"/>
<circle cx="131.8" cy="85" r=".3"/>
<circle cx="134.2" cy="89.2" r=".3"/>
<circle cx="130" cy="89.8" r=".3"/>
<circle cx="148.2" cy="111.6" r=".3"/>
<circle cx="139.8" cy="107.4" r=".3"/>
<circle cx="147.6" cy="111.6" r=".3"/>
<circle cx="136.8" cy="111.6" r=".3"/>
<circle cx="136.8" cy="110.4" r=".3"/>
<circle cx="158.4" cy="108" r=".3"/>
<circle cx="145" cy="85.6" r=".3"/>
<circle cx="160.6" cy="85.6" r=".3"/>
<circle cx="152.3" cy="104.4" r=".3"/>
<circle cx="134.8" cy="88.6" r=".3"/>
<circle cx="156.6" cy="107.4" r=".3"/>
<circle cx="156.6" cy="108" r=".3"/>
<circle cx="132.6" cy="110.4" r=".3"/>
<circle cx="160.2" cy="108" r=".3"/>
<circle cx="148.6" cy="86.8" r=".3"/>
<circle cx="158.2" cy="85" r=".3"/>
<circle cx="132.6" cy="111.6" r=".3"/>
<circle cx="153.6" cy="107.4" r=".3"/>
<circle cx="153" cy="109.2" r=".3"/>
<circle cx="160.2" cy="108.6" r=".3"/>
<circle cx="140.2" cy="88" r=".3"/>
<circle cx="135.4" cy="88.6" r=".3"/>
<circle cx="149.2" cy="85.6" r=".3"/>
<circle cx="153.4" cy="85.6" r=".3"/>
<circle cx="142" cy="89.2" r=".3"/>
<circle cx="141" cy="109.8" r=".3"/>
<circle cx="145" cy="89.2" r=".3"/>
<circle cx="140.4" cy="110.4" r=".3"/>
<circle cx="148" cy="88.6" r=".3"/>
<circle cx="151.6" cy="87.4" r=".3"/>
<circle cx="166.4" cy="111" r=".3"/>
<circle cx="138" cy="108.6" r=".3"/>
<circle cx="125.8" cy="91" r=".3"/>
<circle cx="136.2" cy="108.6" r=".3"/>
<circle cx="144.4" cy="87.4" r=".3"/>
<circle cx="137.2" cy="88.6" r=".3"/>
<circle cx="138.4" cy="86.8" r=".3"/>
<circle cx="143.8" cy="88" r=".3"/>
<circle cx="157.2" cy="111.6" r=".3"/>
<circle cx="133.8" cy="108" r=".3"/>
<circle cx="138" cy="110.4" r=".3"/>
<circle cx="147.4" cy="88.6" r=".3"/>
<circle cx="143.2" cy="85.6" r=".3"/>
<circle cx="152.3" cy="105" r=".3"/>
<circle cx="135.6" cy="108.6" r=".3"/>
<circle cx="137.4" cy="108" r=".3"/>
<circle cx="140.4" cy="106.8" r=".3"/>
<circle cx="133" cy="87.4" r=".3"/>
<circle cx="147" cy="111" r=".3"/>
<circle cx="138.6" cy="106.8" r=".3"/>
<circle cx="146.8" cy="86.8" r=".3"/>
<circle cx="131.4" cy="110.4" r=".3"/>
<circle cx="159.6" cy="111.6" r=".3"/>
<circle cx="137.8" cy="85.6" r=".3"/>
<circle cx="137.4" cy="110.4" r=".3"/>
<circle cx="139.8" cy="110.4" r=".3"/>
<circle cx="155.1" cy="99.4" r=".3"/>
<circle cx="135.4" cy="86.2" r=".3"/>
<circle cx="134.8" cy="88" r=".3"/>
<circle cx="132.6" cy="106.8" r=".3"/>
<circle cx="138" cy="106.2" r=".3"/>
<circle cx="133.6" cy="89.2" r=".3"/>
<circle cx="154.6" cy="91.2" r=".3"/>
<circle cx="135.4" cy="89.8" r=".3"/>
<circle cx="136" cy="91" r=".3"/>
<circle cx="157.6" cy="87.4" r=".3"/>
<circle cx="158.2" cy="88.6" r=".3"/>
<circle cx="144.6" cy="110.4" r=".3"/>
<circle cx="148.8" cy="109.2" r=".3"/>
<circle cx="153" cy="111" r=".3"/>
<circle cx="154.8" cy="111" r=".3"/>
<circle cx="133.8" cy="111" r=".3"/>
<circle cx="147.6" cy="109.2" r=".3"/>
<circle cx="152.4" cy="111.6" r=".3"/>
<circle cx="141.6" cy="108" r=".3"/>
<circle cx="135.4" cy="87.4" r=".3"/>
<circle cx="139.6" cy="88.6" r=".3"/>
<circle cx="160.8" cy="108.6" r=".3"/>
<circle cx="156.4" cy="89.2" r=".3"/>
<circle cx="154" cy="91.2" r=".3"/>
<circle cx="139.8" cy="108" r=".3"/>
<circle cx="139" cy="85.6" r=".3"/>
<circle cx="155.4" cy="109.2" r=".3"/>
<circle cx="132.6" cy="111" r=".3"/>
<circle cx="140.4" cy="108" r=".3"/>
<circle cx="133.8" cy="111.6" r=".3"/>
<circle cx="147.4" cy="89.2" r=".3"/>
<circle cx="130" cy="90.4" r=".3"/>
<circle cx="159.4" cy="86.2" r=".3"/>
<circle cx="167" cy="107.4" r=".3"/>
<circle cx="138.4" cy="88.6" r=".3"/>
<circle cx="134.8" cy="87.4" r=".3"/>
<circle cx="140.8" cy="88.6" r=".3"/>
<circle cx="134.4" cy="108" r=".3"/>
<circle cx="152.2" cy="86.8" r=".3"/>
<circle cx="160" cy="88" r=".3"/>
<circle cx="152.8" cy="88.6" r=".3"/>
<circle cx="158.8" cy="86.8" r=".3"/>
<circle cx="125.8" cy="90.4" r=".3"/>
<circle cx="146.2" cy="88.6" r=".3"/>
<circle cx="142.8" cy="111.6" r=".3"/>
<circle cx="151.8" cy="109.8" r=".3"/>
<circle cx="145.6" cy="85.6" r=".3"/>
<circle cx="143.8" cy="89.2" r=".3"/>
<circle cx="146.2" cy="86.8" r=".3"/>
<circle cx="133" cy="86.8" r=".3"/>
<circle cx="135.4" cy="88" r=".3"/>
<circle cx="155.1" cy="98.8" r=".3"/>
<circle cx="160.2" cy="109.8" r=".3"/>
<circle cx="142.8" cy="111" r=".3"/>
<circle cx="166.7" cy="88" r=".3"/>
<circle cx="134.2" cy="88.6" r=".3"/>
<circle cx="148.6" cy="87.4" r=".3"/>
<circle cx="159.6" cy="108.6" r=".3"/>
<circle cx="155.2" cy="89.2" r=".3"/>
<circle cx="160" cy="85.6" r=".3"/>
<circle cx="150.4" cy="89.2" r=".3"/>
<circle cx="139.8" cy="106.8" r=".3"/>
<circle cx="149.2" cy="87.4" r=".3"/>
<circle cx="137.8" cy="86.8" r=".3"/>
<circle cx="155.2" cy="86.8" r=".3"/>
<circle cx="131.8" cy="88.6" r=".3"/>
<circle cx="157" cy="85.6" r=".3"/>
<circle cx="143.2" cy="86.8" r=".3"/>
<circle cx="160" cy="86.8" r=".3"/>
<circle cx="149.4" cy="111" r=".3"/>
<circle cx="141" cy="108.6" r=".3"/>
<circle cx="145.2" cy="109.2" r=".3"/>
<circle cx="149.8" cy="87.4" r=".3"/>
<circle cx="144.6" cy="109.8" r=".3"/>
<circle cx="149.4" cy="109.2" r=".3"/>
<circle cx="159" cy="108" r=".3"/>
<circle cx="145.2" cy="110.4" r=".3"/>
<circle cx="151.8" cy="110.4" r=".3"/>
<circle cx="153.6" cy="108.6" r=".3"/>
<circle cx="142" cy="88.6" r=".3"/>
<circle cx="152.2" cy="88" r=".3"/>
<circle cx="142" cy="86.2" r=".3"/>
<circle cx="126" cy="108" r=".3"/>
<circle cx="155.8" cy="88" r=".3"/>
<circle cx="154.6" cy="88" r=".3"/>
<circle cx="154.1" cy="103.2" r=".3"/>
<circle cx="139.8" cy="111.6" r=".3"/>
<circle cx="140.8" cy="87.4" r=".3"/>
<circle cx="166.7" cy="85.6" r=".3"/>
<circle cx="140.2" cy="86.2" r=".3"/>
<circle cx="160.2" cy="111" r=".3"/>
<circle cx="149.2" cy="89.2" r=".3"/>
<circle cx="136" cy="85.6" r=".3"/>
<circle cx="132.4" cy="85.6" r=".3"/>
<circle cx="145.6" cy="88" r=".3"/>
<circle cx="147" cy="111.6" r=".3"/>
<circle cx="150" cy="110.4" r=".3"/>
<circle cx="126" cy="111.6" r=".3"/>
<circle cx="141.6" cy="110.4" r=".3"/>
<circle cx="136" cy="90.4" r=".3"/>
<circle cx="154" cy="87.4" r=".3"/>
<circle cx="154.6" cy="85.6" r=".3"/>
<circle cx="135" cy="111" r=".3"/>
<circle cx="155.4" cy="107.4" r=".3"/>
<circle cx="141.6" cy="109.2" r=".3"/>
<circle cx="144" cy="111.6" r=".3"/>
<circle cx="158.8" cy="88.6" r=".3"/>
<circle cx="144.4" cy="86.8" r=".3"/>
<circle cx="147.4" cy="85.6" r=".3"/>
<circle cx="141" cy="108" r=".3"/>
<circle cx="136.2" cy="111.6" r=".3"/>
<circle cx="154.2" cy="109.2" r=".3"/>
<circle cx="129.4" cy="91" r=".3"/>
<circle cx="131.4" cy="106.8" r=".3"/>
<circle cx="143.8" cy="85.6" r=".3"/>
<circle cx="137.4" cy="111.6" r=".3"/>
<circle cx="161.2" cy="89.2" r=".3"/>
<circle cx="154.2" cy="111.6" r=".3"/>
<circle cx="151.8" cy="92.4" r=".3"/>
<circle cx="139.2" cy="108" r=".3"/>
<circle cx="140.4" cy="111.6" r=".3"/>
<circle cx="133" cy="86.2" r=".3"/>
<circle cx="158.4" cy="111" r=".3"/>
<circle cx="159.6" cy="109.8" r=".3"/>
<circle cx="142.9" cy="104.2" r=".3"/>
<circle cx="146.3" cy="100.2" r=".3"/>
<circle cx="149.8" cy="103.4" r=".3"/>
<circle cx="127.1" cy="101.4" r=".3"/>
<circle cx="127.1" cy="100.6" r=".3"/>
<circle cx="126.9" cy="97" r=".3"/>
<circle cx="126.9" cy="96.1" r=".3"/>
<circle cx="164.2" cy="102.6" r=".3"/>
<circle cx="148.8" cy="90.4" r=".3"/>
<circle cx="164.2" cy="100.1" r=".3"/>
<circle cx="146.2" cy="92.7" r=".3"/>
<circle cx="146.6" cy="91.8" r=".3"/>
<circle cx="164.2" cy="98.2" r=".3"/>
<circle cx="164.2" cy="101.2" r=".3"/>
<circle cx="143.8" cy="90.4" r=".3"/>
<circle cx="154.1" cy="96" r=".3"/>
<circle cx="153.6" cy="98.8" r=".3"/>
<circle cx="142" cy="92.3" r=".3"/>
<circle cx="147.6" cy="96" r=".3"/>
<circle cx="148.4" cy="96" r=".3"/>
<circle cx="142.3" cy="91.6" r=".3"/>
<circle cx="132.5" cy="95.7" r=".3"/>
<circle cx="132.5" cy="97.5" r=".3"/>
<circle cx="130.7" cy="101.5" r=".3"/>
<circle cx="131" cy="100.7" r=".3"/>
<circle cx="160.2" cy="102.8" r=".3"/>
<circle cx="160.2" cy="101.6" r=".3"/>
<circle cx="160.3" cy="100.1" r=".3"/>
<circle cx="160.4" cy="98.2" r=".3"/>
<circle cx="127.9" cy="99.2" r=".3"/>
</g>
<g fill="none" stroke="#4d7fc4" stroke-width=".21">
<path d="M126.9 97h.6l.6 .5h.5M128.6 95.4h-.5l-.7 .7h-.5M131.3 95.4h1l.2 .3M132.5 97.5h-1.2M137.2 96.5l.1 .4M137.4 92v2.2l.1 .1h3.4M138.4 93.2v.1M138.5 92l-.1 .1M139.4 92h.1M139.5 92.5l-.1 1M139.5 91h-2l-1.1 1.1v7.1l2.9 2.9h12l2.3-2.3v-1M139.9 92.5h.6"/>
<path d="M139.9 91v-.5h-2.5l-1.4 1.4v7.5l3.1 3.1h12.6l2.5-2.5-.1-4M140.4 93.7l-.6 .6M140.5 91l-.1 .5h-1M140.5 92.5l-.1 1M140.9 94.3l.2 .2-.1 2M141 91.5l1.3 .1M141 92h-.5v.5M141 91h-.1M141 99v-.2l-.8 .8h-2.9M142 92.3l-.2-.2-.5 .4h-.4M143.8 90.4l.5 .5h1.1M144 96.4h.1"/>
<path d="M144.1 98.8h-.1M144.2 91.9h1.7l.5-.7h.4l.2 .2h1.1l.4 .4v.9M144.2 91.9h.1M144.7 93.4h.7M144.7 93.4v.9l2.5 2.5h1.9l.3-.3-.4-.4v-1.2l-.2-.2-.1-1.1M145.4 91.4l-1.6-.1-2.9 3M145.4 92.4h-.7l-.5 .5 .5 .5M146.6 94.3v.7l1 1M146.6 94.2l-.1 .1M146.6 91.8l1.1 .1M147.7 90.9h.6l.8 .8 11.1 .1 .2 .2-.2 .2h-6.2l-.4 .5v2.5l-.8 .8v3.3l-2.1 2.1h-6.3l-.3-.3h-5.3l-2-2.1v-1.6l3.1-3.1M147.7 93.4h.8l.2 .2"/>
<path d="M147.7 92.4h-1.1l-.4 .3M147.7 93.9v1.4l.7 .7M147.8 92.9h-.1M148.5 92.7h.1M148.5 92.7l-.2 .2h-1.1l-.3 .3h-.3l-.7 .7h-.5M148.5 92.7h.6M148.7 93.6l.2-.2h4.1l.6 .6M148.8 90.4l-2.2 .1M149.5 95.8l.1 .1M150.6 98.5l-.3 .3M151.1 94.2h1.5M160.4 98.2l1 .1"/>
<path d="M164.3 98.2l-2.2 .1M127.1 101.4l.2-.1h.7l.9 .8M128.7 102.2h.2M128.7 100.1h.2M128.9 100l-.9 .8h-.6l-.3-.2M130.7 101.5h.4l.4 .6M131.5 100v.4l-.3 .3h-.2M136.7 101v2.4l1 1M160.2 102.8l.7 .7h.4M160.3 101.6h1M160.3 100.1h1M162 100.1h2.2"/>
<path d="M164.2 101.2l-.5 .4h-1.7M164.2 102.6h-.5l-.8 .9h-.9"/>
</g>
<path d="M138.4 92.1v1.2M138.5 92h.9M139.4 91.5v.5M140.5 91l2.1-.1 .4 .4M142.1 98.8h1.9M144.2 91.9h-.2l-.6 .6v1.3l5 5h1.9M144.2 98.8h-.1v.2l1.3 1.3v.6M144.9 95.4h.1M149.5 94.2v1.6M149.6 95.9l.7 .8v3.7l-.4 .5h-4.5M145.4 100.9h.1" fill="none" stroke="#4d7fc4" stroke-width=".3"/>
<path d="M126.2 99.1v5.7l.3 .3h12.2l.9-.9h9.3l.9-.8M126.9 99.1l1 .1M142.1 96.4h1.9M143.8 96.4l2.5 2.5v1.3" fill="none" stroke="#4d7fc4" stroke-width=".4"/>
<g fill="#4d7fc4">
<path d="M137.4 91.9l.2 .1 .1 .5-.1 1.9 3.2-.1 .4-.6h-.6v.6h-.5l.1-1.3 .4 .3h.6l1.5-.4 .1 1.2 .9 .9a1.38 1.38 0 0 1-1.3 .3h-1.1v1.3l-1.1 .1 .1 .4 .4 .4-.1 .2a.71 .71 0 0 0-.4 .8l1 .1v1.3l1.7-.1-.4 1h1.7l.1 .4-1.8 .1-.1 .2h-2.9l-2.1-2.2h2.8l.1 .4 .5 .2v-.8h-.6v.2h-2.8l-.4-.3v-3.1h3.2v.2h.6v-.8l-.4 .2-.2 .4h-3.2l.1-3.6z"/>
<path d="M150.5 101.2h.8l-.3 .3h-.5l-.1-.1z"/>
<path d="M150.2 95l.7 .2 1-.2 .1 .2-.2 .5 1.2 .1v1.1h.6v1a.9 .9 0 0 0-.7 1.4v.3l-.9 .9h-.2v-3.3l-.2-.6-.7-.3h.9a.71 .71 0 0 0 .8 .6v-.7l-1.7 .1-.7-1z"/>
<path d="M147.6 96.8l1.3-.1-.1 1.3-.2 .1-1-1.1z"/>
<path d="M145.3 94.6h.6v.6l-.6-.4z"/>
<path d="M125.2 84.5l42.3-.1 .1 .1-.1 27.7h-42.2l-.1-2.8h2a1.35 1.35 0 0 0 1.3 1.5 1.35 1.35 0 0 0 1.5-1.4h32.4v.2a1.35 1.35 0 0 0 2.1 1.1 1.35 1.35 0 0 0 0-2.4 1.35 1.35 0 0 0-2.1 1.1l-32.4-.1a1.35 1.35 0 0 0-1.4-1.3 1.35 1.35 0 0 0-1.4 1.3h-2v-10.7h.2l.1 6.2 .2 .3 .6 .6h12.5l.3-.2 .8-.7h9.1l1-.8a.97 .97 0 0 0 .6-1h1.2l.5-.3h7.1v.2a.87 .87 0 0 0 .8 .6l.8 .7h1.3l.9-.3 .6-.6a.9 .9 0 0 0 1.1-.4 .9 .9 0 0 0-.2-1.2 1.1 1.1 0 0 0 .1-1.2 .81 .81 0 0 0 0-1.1 .81 .81 0 0 0-1.1-.1l-.9 .1-.3-.3 .4-.4h.8a.82 .82 0 0 0 1.1 0 .82 .82 0 0 0 0-1.2 .82 .82 0 0 0-1.1 0h-.9l-.4-.3-1.6 .1a.85 .85 0 0 0-1.2 .8 .85 .85 0 0 0 1.2 .8l.1 .2-.2 .1a.88 .88 0 0 0-1.1 .4 .88 .88 0 0 0 .3 1.1v.1a1.07 1.07 0 0 0-.3 1.4l-.2 .5h-7.1l2.5-2.5v-3.9a.86 .86 0 0 0-.2-1 .86 .86 0 0 0-1-.2l.2-1.1-.3-.5-.4-.1-1.1 .1-.5-.4-.9 .1a.41 .41 0 0 1-.5 .1 .41 .41 0 0 1-.2-.5v-.9l-.8-.1v-.3l.1-.1h.7l-.1-.3a.46 .46 0 0 1-.2-.8 .83 .83 0 0 0-.5-.7 .83 .83 0 0 0-.9 .1l-1.9-.1-.5 .5-1.1 .1a.92 .92 0 0 0-.9-.7 .92 .92 0 0 0-.9 .7h-2.3l-.6-.4h-2.6l-1.9 1.6-.1 .3v7.8l3.5 3.5h9.8l.1 .1-.2 .3h-9.1l-1.1 .9h-11.4l-.1-2.1 .9-.4 .2 .1a.58 .58 0 0 0 .4 .8l1.1-.1 .2-.2 .2-.7 1.1 1h1l.3-.1 .1-.3-.1-.7-.6-.5 .6-.8 .1-.7-.4-.4h-.9a.57 .57 0 0 0-.5 .7 .97 .97 0 0 0-.5 .9l-.3 .8-.3-.2-.6-.1-.2-.3a.68 .68 0 0 1 .8-.5l.2-.3v-.7l-.3-.3h-.6l-.2-.6-.4-.3 1.2-.3 .1-.9-.4-.4h-.9l-.3-.4 .3-.3 1.2-.1 .1-.8h.9v.5l.3 .4h1.2l.5 .5-.4 .3h-1.3l-.3 .3 .1 .8 .3 .2h1.1a.88 .88 0 0 0 1.1-.1 .88 .88 0 0 0 .2-1.1l-.5-.5a.88 .88 0 0 0 .6-1.1 .88 .88 0 0 0-1.1-.6l-1.4-.1-.4 .5h-.9l-.4-.5h-.9l-.8 .7a.92 .92 0 0 0-1.1 .1 .92 .92 0 0 0-.2 1.1 .88 .88 0 0 0 .3 1 .88 .88 0 0 0 1 .1l.6 .5v.2l-.4 .1-.3-.3h-1.5l-.4 .5h-.2v-11.6h2.3v.2a1.35 1.35 0 0 0 1.6 1.2 1.35 1.35 0 0 0 1.1-1.5h32.4v.2a1.35 1.35 0 0 0 2.1 1.1 1.35 1.35 0 0 0 0-2.4 1.35 1.35 0 0 0-2.1 1.1h-32.4v-.1a1.35 1.35 0 0 0-1.4-1.1 1.35 1.35 0 0 0-1.3 1.3h-2.3z"/>
</g>
</svg>
